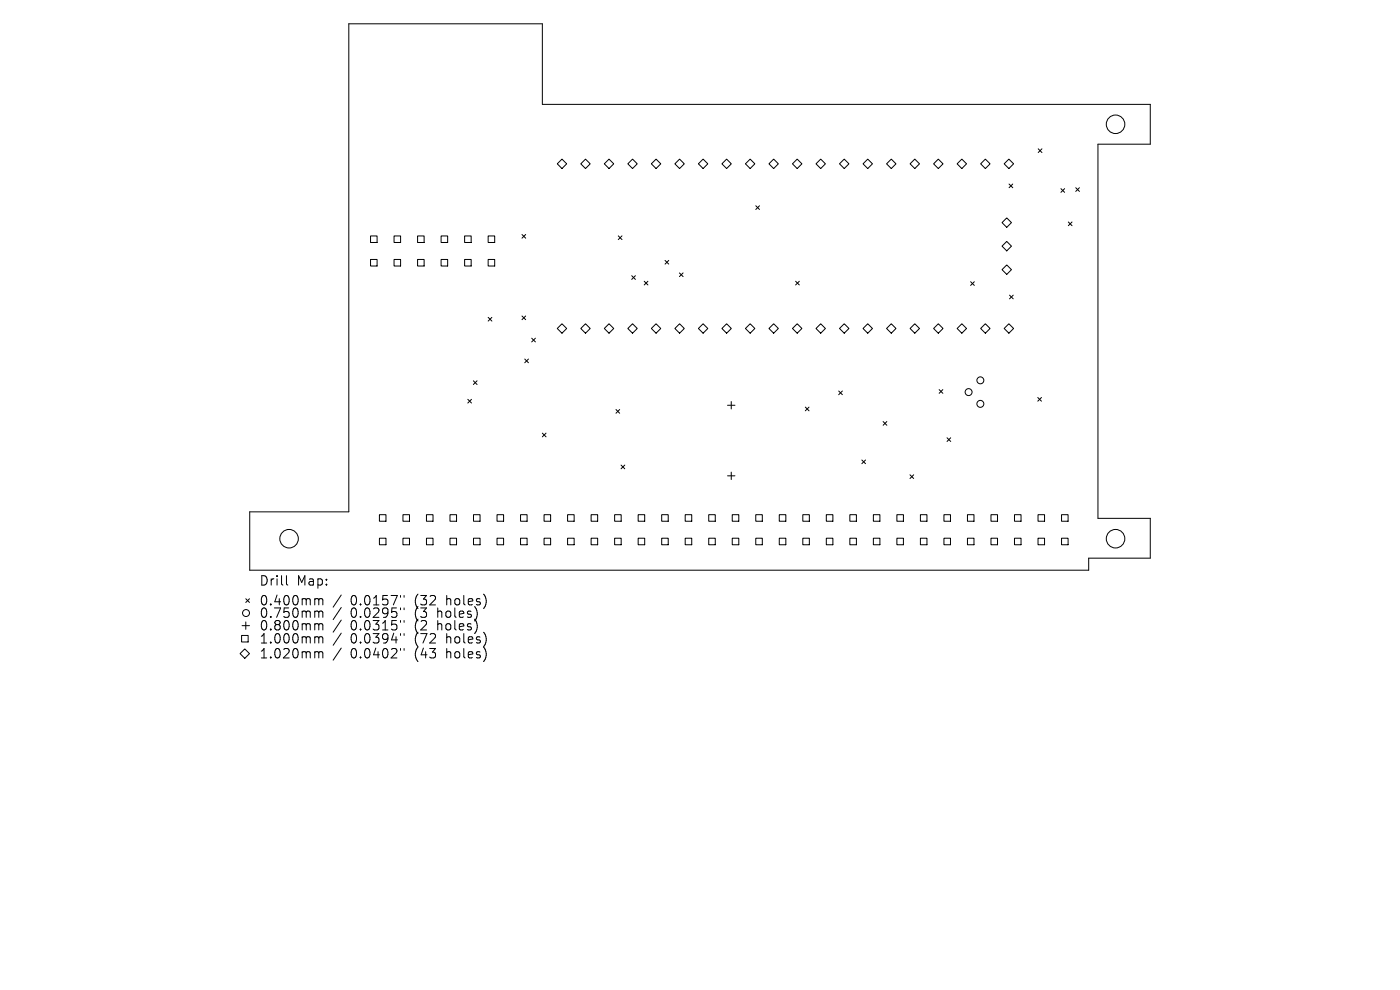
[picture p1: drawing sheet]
<svg xmlns="http://www.w3.org/2000/svg" width="297mm" height="210mm" viewBox="0 0 297 210" stroke-linecap="round" stroke-linejoin="round" font-family="sans-serif">
<defs><g id="words">
<g font-size="2.8">
<text x="54.9" y="124.5">Drill</text>
<text x="62.9" y="124.5">Map:</text>
<text x="54.9" y="128.7">0.400mm</text>
<text x="54.9" y="131.3">0.750mm</text>
<text x="74.4" y="128.7">0.0157&quot;</text>
<text x="74.4" y="131.3">0.0295&quot;</text>
<text x="88.1" y="128.7">(32</text>
<text x="88.1" y="131.3">(3</text>
<text x="93.1" y="131.3">holes)</text>
<text x="95" y="128.7">holes)</text>
<text x="54.9" y="134">0.800mm</text>
<text x="54.9" y="136.8">1.000mm</text>
<text x="74.4" y="134">0.0315&quot;</text>
<text x="74.4" y="136.8">0.0394&quot;</text>
<text x="88.1" y="134">(2</text>
<text x="88.1" y="136.8">(72</text>
<text x="93.1" y="134">holes)</text>
<text x="95" y="136.8">holes)</text>
<text x="54.9" y="140">1.020mm</text>
<text x="74.4" y="140">0.0402&quot;</text>
<text x="88.1" y="140">(43</text>
<text x="95" y="140">holes)</text>
</g>
</g></defs>
<g fill="none" stroke="#000" stroke-width=".21">
<path d="M74 5h41.1v17.1h128.9v8.5h-11.1v79.4h11.1v8.4h-13v2.6h-178v-12.4h21zM118.2 34.8l1-1 1 1-1 1zM123.2 34.8l1-1 1 1-1 1zM128.2 34.8l1-1 1 1-1 1zM133.2 34.8l1-1 1 1-1 1zM138.2 34.8l1-1 1 1-1 1zM143.2 34.8l1-1 1 1-1 1zM148.2 34.8l1-1 1 1-1 1zM153.1 34.8l1-1 1.1 1-1.1 1zM159.1 33.8l1 1-1 1-1-1zM163.1 34.8l1-1 1 1-1 1zM168.1 34.8l1-1 1 1-1 1z"/>
<path d="M174.1 33.8l1 1-1 1-1-1zM179.1 33.8l1 1-1 1-1-1zM183.1 34.8l1-1 1 1-1 1zM188.1 34.8l1-1 1 1-1 1zM193.1 34.8l1-1 1 1-1 1zM198.1 34.8l1-1 1 1-1 1zM203 34.8l1-1 1 1-1 1zM208 34.8l1-1 1 1-1 1zM213 34.8l1-1 1 1-1 1zM214.1 39l.8 .8M214.9 39l-.8 .8M220.3 31.6l.7 .8"/>
<path d="M221 31.6l-.7 .8M228.2 39.8l.8 .8M229 39.8l-.8 .8M78.6 50h1.4v1.4h-1.4zM78.6 55h1.4v1.4h-1.4zM83.6 50h1.4v1.4h-1.4zM83.6 55h1.4v1.4h-1.4zM88.6 50h1.4v1.4h-1.4zM88.6 55h1.4v1.4h-1.4zM93.6 50h1.4v1.4h-1.4zM93.6 55h1.4v1.4h-1.4zM98.6 50h1.4v1.4h-1.4z"/>
<path d="M98.6 55h1.4v1.4h-1.4zM103.6 50h1.3v1.4h-1.3zM103.6 55h1.3v1.4h-1.3zM110.7 49.7l.8 .8M111.5 49.7l-.8 .8M131.2 50l.8 .8M132 50l-.8 .8M134 58.5l.8 .8M134.8 58.5l-.8 .8M136.7 59.7l.8 .7M137.5 59.7l-.8 .7M141.1 55.2l.8 .8"/>
<path d="M141.9 55.2l-.8 .8M144.1 57.9l.8 .8M144.9 57.9l-.8 .8M160.3 43.7l.8 .7M161.1 43.7l-.8 .7M168.8 59.7l.8 .7M169.6 59.7l-.8 .7M205.9 59.8l.8 .7M206.7 59.8l-.8 .7M212.6 47.2l1-1 1 1-1 1zM212.6 52.2l1-1 1 1-1 1zM212.6 57.2l1-1 1 1-1 1z"/>
<path d="M225.1 40l.8 .8M225.9 40l-.8 .8M226.6 47.1l.8 .8M227.4 47.1l-.8 .8M103.6 67.3l.7 .8M104.3 67.3l-.7 .8M110.7 67l.8 .8M111.3 76.2l.8 .8M111.5 67l-.8 .8M112.1 76.2l-.8 .8M112.8 71.7l.8 .8M113.6 71.7l-.8 .8"/>
<path d="M118.2 69.7l1-1 1 1-1 1zM124.2 68.7l1 1-1 1-1-1zM128.2 69.7l1-1 1 1-1 1zM133.2 69.7l1-1 1 1-1 1zM138.2 69.7l1-1 1 1-1 1zM143.2 69.7l1-1 1 1-1 1zM148.2 69.7l1-1 1 1-1 1zM153.1 69.7l1-1 1.1 1-1.1 1zM159.1 68.7l1 1-1 1-1-1zM163.1 69.7l1-1 1 1-1 1zM168.1 69.7l1-1 1 1-1 1zM174.1 68.7l1 1-1 1-1-1z"/>
<path d="M179.1 68.7l1 1-1 1-1-1zM183.1 69.7l1-1 1 1-1 1zM189.1 68.7l1 1-1 1-1-1zM194.1 68.7l1 1-1 1-1-1zM198.1 69.7l1-1 1 1-1 1zM203 69.7l1-1 1 1-1 1zM209 68.7l1 1-1 1-1-1zM214 68.7l1 1-1 1-1-1zM214.2 62.6l.8 .8M215 62.6l-.8 .8M99.2 84.7l.8 .8M100 84.7l-.8 .8"/>
<path d="M100.4 80.8l.8 .8M101.2 80.8l-.8 .8M115.1 91.9l.7 .8M115.8 91.9l-.7 .8M130.7 86.9l.8 .8M131.5 86.9l-.8 .8M131.8 98.7l.7 .7M132.5 98.7l-.7 .7M154.3 86h1.6M155.1 85.2v1.6M170.8 86.4l.8 .7M171.6 86.4l-.8 .7"/>
<path d="M177.9 82.9l.8 .8M178.7 82.9l-.8 .8M182.8 97.6l.8 .8M183.6 97.6l-.8 .8M187.3 89.4l.8 .8M188.1 89.4l-.8 .8M199.2 82.6l.8 .8M200 82.6l-.8 .8M200.9 92.9l.8 .7M201.7 92.9l-.8 .7M220.2 84.3l.7 .8M220.9 84.3l-.7 .8"/>
<path d="M80.5 109.2h1.4v1.4h-1.4zM80.5 114.2h1.4v1.4h-1.4zM85.5 109.2h1.4v1.4h-1.4zM85.5 114.2h1.4v1.4h-1.4zM90.5 109.2h1.4v1.4h-1.4zM90.5 114.2h1.4v1.4h-1.4zM95.5 109.2h1.4v1.4h-1.4zM95.5 114.2h1.4v1.4h-1.4zM100.5 109.2h1.3v1.4h-1.3zM100.5 114.2h1.3v1.4h-1.3zM105.4 109.2h1.4v1.4h-1.4zM105.4 114.2h1.4v1.4h-1.4z"/>
<path d="M110.4 109.2h1.4v1.4h-1.4zM110.4 114.2h1.4v1.4h-1.4zM115.4 109.2h1.4v1.4h-1.4zM115.4 114.2h1.4v1.4h-1.4zM120.4 109.2h1.4v1.4h-1.4zM120.4 114.2h1.4v1.4h-1.4zM125.4 109.2h1.4v1.4h-1.4zM125.4 114.2h1.4v1.4h-1.4zM130.4 109.2h1.4v1.4h-1.4zM130.4 114.2h1.4v1.4h-1.4zM135.4 109.2h1.4v1.4h-1.4zM135.4 114.2h1.4v1.4h-1.4z"/>
<path d="M140.4 109.2h1.4v1.4h-1.4zM140.4 114.2h1.4v1.4h-1.4zM145.4 109.2h1.3v1.4h-1.3zM145.4 114.2h1.3v1.4h-1.3zM150.4 109.2h1.3v1.4h-1.3zM150.4 114.2h1.3v1.4h-1.3zM154.3 100.9h1.6M155.1 100.2v1.5M155.3 109.2h1.4v1.4h-1.4zM155.3 114.2h1.4v1.4h-1.4zM160.3 109.2h1.4v1.4h-1.4zM160.3 114.2h1.4v1.4h-1.4z"/>
<path d="M165.3 109.2h1.4v1.4h-1.4zM165.3 114.2h1.4v1.4h-1.4zM170.3 109.2h1.4v1.4h-1.4zM170.3 114.2h1.4v1.4h-1.4zM175.3 109.2h1.4v1.4h-1.4zM175.3 114.2h1.4v1.4h-1.4zM180.3 109.2h1.4v1.4h-1.4zM180.3 114.2h1.4v1.4h-1.4zM185.3 109.2h1.4v1.4h-1.4zM185.3 114.2h1.4v1.4h-1.4zM190.3 109.2h1.4v1.4h-1.4zM190.3 114.2h1.4v1.4h-1.4z"/>
<path d="M193 100.7l.8 .8M193.8 100.7l-.8 .8M195.3 109.2h1.3v1.4h-1.3zM195.3 114.2h1.3v1.4h-1.3zM200.2 109.2h1.4v1.4h-1.4zM200.2 114.2h1.4v1.4h-1.4zM205.2 109.2h1.4v1.4h-1.4zM205.2 114.2h1.4v1.4h-1.4zM210.2 109.2h1.4v1.4h-1.4zM210.2 114.2h1.4v1.4h-1.4zM215.2 109.2h1.4v1.4h-1.4zM215.2 114.2h1.4v1.4h-1.4z"/>
<path d="M220.2 109.2h1.4v1.4h-1.4zM220.2 114.2h1.4v1.4h-1.4zM225.2 109.2h1.4v1.4h-1.4zM225.2 114.2h1.4v1.4h-1.4zM50.9 138.7l1-1 1 1-1 1zM51.3 134.8h1.3v1.4h-1.3zM51.4 132.7h1.5M52.1 127l.8 .8M52.1 131.9v1.6M52.9 127l-.8 .8M60.8 122.1v1.7l.3 .3M67.1 127l.4 .1 .1 .2"/>
<path d="M67.1 129.6h.2l.3 .3M67.1 132.3h.2l.3 .3M67.1 135.1h.2l.3 .3M67.1 138.2h.2l.3 .3M67.6 127.3l.3-.3 .5 .1 .1 1.2M67.6 127.3v1M67.6 129.9v1.1M67.6 132.6v1M67.6 135.4v1M67.6 138.5v1.1M67.6 129.9l.3-.3 .5 .1 .1 1.3M67.6 132.6l.3-.3 .5 .1 .1 1.2"/>
<path d="M67.6 135.4l.3-.3 .5 .1 .1 1.2M67.6 138.5l.3-.3 .5 .1 .1 1.3M72.4 126.2l-1.7 2.6M72.4 128.9l-1.7 2.5M72.4 131.5l-1.7 2.6M72.4 134.3l-1.7 2.6M72.4 137.5l-1.7 2.5M85 126.3v.4M85 129v.3M85 131.6v.4M85 134.4v.4M85 137.6v.3"/>
<path d="M85.7 126.3v.4M85.7 129v.3M85.7 131.6v.4M85.7 134.4v.4M85.7 137.6v.3"/>
<circle cx="236.7" cy="26.4" r="1.96"/>
<circle cx="205.5" cy="83.2" r=".74"/>
<circle cx="208" cy="85.7" r=".74"/>
<circle cx="208" cy="80.7" r=".74"/>
<circle cx="61.3" cy="114.3" r="1.96"/>
<circle cx="236.7" cy="114.3" r="1.96"/>
<circle cx="52.2" cy="130" r=".74"/>
</g>
<use href="#words"/>
</svg>
